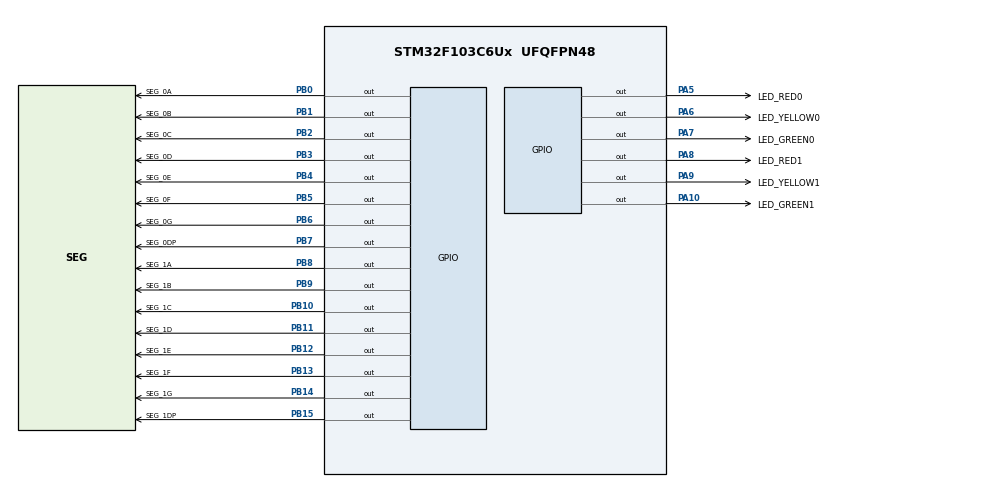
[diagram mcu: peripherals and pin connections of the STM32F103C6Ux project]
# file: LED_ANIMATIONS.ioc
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Mcu.Family=STM32F1
Mcu.Name=STM32F103C6Ux
Mcu.Package=UFQFPN48
NVIC.PriorityGroup=NVIC_PRIORITYGROUP_4
PA10.GPIO_Label=LED_GREEN1
PA10.Signal=GPIO_Output
PA5.GPIO_Label=LED_RED0
PA5.Signal=GPIO_Output
PA6.GPIO_Label=LED_YELLOW0
PA6.Signal=GPIO_Output
PA7.GPIO_Label=LED_GREEN0
PA7.Signal=GPIO_Output
PA8.GPIO_Label=LED_RED1
PA8.Signal=GPIO_Output
PA9.GPIO_Label=LED_YELLOW1
PA9.Signal=GPIO_Output
PB0.GPIO_Label=SEG_0A
PB0.Signal=GPIO_Output
PB1.GPIO_Label=SEG_0B
PB1.Signal=GPIO_Output
PB10.GPIO_Label=SEG_1C
PB10.Signal=GPIO_Output
PB11.GPIO_Label=SEG_1D
PB11.Signal=GPIO_Output
PB12.GPIO_Label=SEG_1E
PB12.Signal=GPIO_Output
PB13.GPIO_Label=SEG_1F
PB13.Signal=GPIO_Output
PB14.GPIO_Label=SEG_1G
PB14.Signal=GPIO_Output
PB15.GPIO_Label=SEG_1DP
PB15.Signal=GPIO_Output
PB2.GPIO_Label=SEG_0C
PB2.Signal=GPIO_Output
PB3.GPIO_Label=SEG_0D
PB3.Signal=GPIO_Output
PB4.GPIO_Label=SEG_0E
PB4.Signal=GPIO_Output
PB5.GPIO_Label=SEG_0F
PB5.Signal=GPIO_Output
PB6.GPIO_Label=SEG_0G
PB6.Signal=GPIO_Output
PB7.GPIO_Label=SEG_0DP
PB7.Signal=GPIO_Output
PB8.GPIO_Label=SEG_1A
PB8.Signal=GPIO_Output
PB9.GPIO_Label=SEG_1B
PB9.Signal=GPIO_Output
ProjectManager.HeapSize=0x200
ProjectManager.StackSize=0x400
ProjectManager.TargetToolchain=STM32CubeIDE
RCC.APB1Freq_Value=8000000
RCC.APB2Freq_Value=8000000
board=custom

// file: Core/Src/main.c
/* USER CODE BEGIN Header */
/**
  ******************************************************************************
  * @file           : main.c
  * @brief          : Main program body
  ******************************************************************************
  * @attention
  *
  * Copyright (c) 2023 STMicroelectronics.
  * All rights reserved.
  *
  * This software is licensed under terms that can be found in the LICENSE file
  * in the root directory of this software component.
  * If no LICENSE file comes with this software, it is provided AS-IS.
  *
  ******************************************************************************
  */
/* USER CODE END Header */
#include "main.h"

/* USER CODE BEGIN Includes */
#include "clock_function.h"
#include "software_timer.h"
/* USER CODE END Includes */

/* USER CODE BEGIN PD */
#define DURATION 1
/* USER CODE END PD */

void SystemClock_Config(void);
static void MX_GPIO_Init(void);

int main(void)
{

  /* MCU Configuration--------------------------------------------------------*/

  /* Reset of all peripherals, Initializes the Flash interface and the Systick. */
  HAL_Init();

  /* Configure the system clock */
  SystemClock_Config();

  /* Initialize all configured peripherals */
  MX_GPIO_Init();
  /* USER CODE BEGIN 2 */
  int currentSecond = 0;
  int currentMinute = 0;
  int currentHour = 0;
  setTimer0(DURATION);
  /* USER CODE END 2 */

  /* Infinite loop */
  /* USER CODE BEGIN WHILE */
  while (1)
  {
	  if (timer0_flag == 1) {
		  currentSecond ++;
		  if (currentSecond >= 60) {
			  currentSecond = 0;
			  currentMinute ++;
		  }
		  if (currentMinute >= 60) {
			  currentMinute = 0;
			  currentHour ++;
		  }
		  if (currentHour >= 12) {
			  currentHour = 0;
		  }
		  setTimer0(DURATION);
	  }
	  clearAllClock();
	  setNumberOnClock(currentSecond / 5);
	  setNumberOnClock(currentMinute / 5);
	  setNumberOnClock(currentHour);
	  runTimer();
	  HAL_Delay(1000);
    /* USER CODE END WHILE */

  }
}

void SystemClock_Config(void)
{
  RCC_OscInitTypeDef RCC_OscInitStruct = {0};
  RCC_ClkInitTypeDef RCC_ClkInitStruct = {0};

  /** Initializes the RCC Oscillators according to the specified parameters
  * in the RCC_OscInitTypeDef structure.
  */
  RCC_OscInitStruct.OscillatorType = RCC_OSCILLATORTYPE_HSI;
  RCC_OscInitStruct.HSIState = RCC_HSI_ON;
  RCC_OscInitStruct.HSICalibrationValue = RCC_HSICALIBRATION_DEFAULT;
  RCC_OscInitStruct.PLL.PLLState = RCC_PLL_NONE;
  if (HAL_RCC_OscConfig(&RCC_OscInitStruct) != HAL_OK)
  {
    Error_Handler();
  }

  /** Initializes the CPU, AHB and APB buses clocks
  */
  RCC_ClkInitStruct.ClockType = RCC_CLOCKTYPE_HCLK|RCC_CLOCKTYPE_SYSCLK
                              |RCC_CLOCKTYPE_PCLK1|RCC_CLOCKTYPE_PCLK2;
  RCC_ClkInitStruct.SYSCLKSource = RCC_SYSCLKSOURCE_HSI;
  RCC_ClkInitStruct.AHBCLKDivider = RCC_SYSCLK_DIV1;
  RCC_ClkInitStruct.APB1CLKDivider = RCC_HCLK_DIV1;
  RCC_ClkInitStruct.APB2CLKDivider = RCC_HCLK_DIV1;

  if (HAL_RCC_ClockConfig(&RCC_ClkInitStruct, FLASH_LATENCY_0) != HAL_OK)
  {
    Error_Handler();
  }
}

static void MX_GPIO_Init(void)
{
  GPIO_InitTypeDef GPIO_InitStruct = {0};

  /* GPIO Ports Clock Enable */
  __HAL_RCC_GPIOA_CLK_ENABLE();

  /*Configure GPIO pin Output Level */
  HAL_GPIO_WritePin(GPIOA, LED_0_Pin|LED_1_Pin|LED_2_Pin|LED_3_Pin
                          |LED_4_Pin|LED_5_Pin|LED_6_Pin|LED_7_Pin
                          |LED_8_Pin|LED_9_Pin|LED_10_Pin|LED_11_Pin, GPIO_PIN_RESET);

  /*Configure GPIO pins : LED_0_Pin LED_1_Pin LED_2_Pin LED_3_Pin
                           LED_4_Pin LED_5_Pin LED_6_Pin LED_7_Pin
                           LED_8_Pin LED_9_Pin LED_10_Pin LED_11_Pin */
  GPIO_InitStruct.Pin = LED_0_Pin|LED_1_Pin|LED_2_Pin|LED_3_Pin
                          |LED_4_Pin|LED_5_Pin|LED_6_Pin|LED_7_Pin
                          |LED_8_Pin|LED_9_Pin|LED_10_Pin|LED_11_Pin;
  GPIO_InitStruct.Mode = GPIO_MODE_OUTPUT_PP;
  GPIO_InitStruct.Pull = GPIO_NOPULL;
  GPIO_InitStruct.Speed = GPIO_SPEED_FREQ_LOW;
  HAL_GPIO_Init(GPIOA, &GPIO_InitStruct);

}

void Error_Handler(void)
{
  __disable_irq();
  while (1)
  {
  }
}
